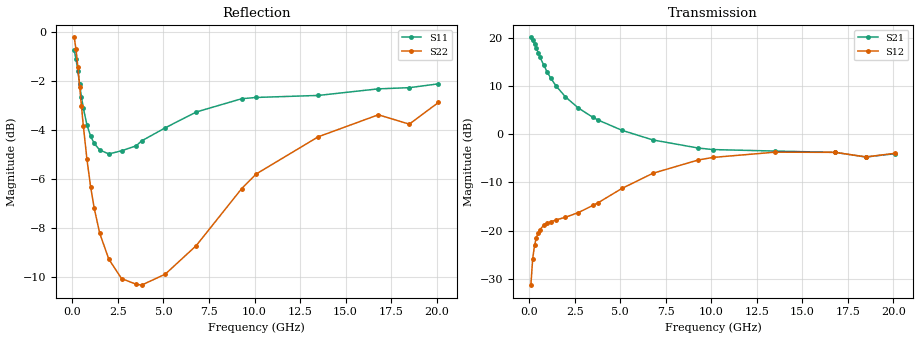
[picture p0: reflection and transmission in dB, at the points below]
!  Infineon Technologies AG
! BFR380L3 , PF131585-7, No.6, Th 09.10.01, soldered on pcb-board, measured with PP GSG850
!  Vce=5.0 V,  Ic=3.0 mA
! Common Emitter S-Parameters:  15. November 2001
#  GHz  S  MA  R  50
! f  S11  S21  S12  S22
! GHz  Mag  Ang  Mag  Ang  Mag  Ang  Mag  Ang
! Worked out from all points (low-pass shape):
!   201 points, 100 MHz to 20.1 GHz, reference 50 ohm
!   highest |S21| = 20.15 dB at 100 MHz (marker M1); lowest = -4.7 dB at 18.5 GHz (marker M2)
!   |S21| within 3 dB of the highest: start of sweep to 482.3 MHz
!   lowest |S11| = -5.0 dB at 2 GHz (marker M3), VSWR 3.59, Z = 14 - j3.21 ohm
!   |S11| at or under -10 dB: nowhere
!   |S22| runs from -10.3 to -0.2 dB; largest |S21 - S12| = 10
!   S11 on the Smith chart (normalised r, x): 100 MHz: 1.35, -5.37; 500 MHz: 0.33, -1.05; 1.2 GHz: 0.29, -0.34; 3.8 GHz: 0.27, +0.27; 9.3 GHz: 0.34, +1.07; 20.1 GHz: 0.99, +2.52
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0.1  0.9182 -19.9  10.17 166.1  0.02707 77.6  0.9756 -10.9
0.2  0.881 -38.7  9.463 153.6  0.05099 69.2  0.9223 -20.7
0.3  0.8326 -56.0  8.684 142.4  0.06991 60.6  0.8495 -28.9
0.4  0.7819 -71.0  7.851 132.9  0.08412 53.8  0.774 -35.5
0.5  0.7367 -84.2  7.068 124.9  0.0946 48.6  0.7051 -40.7
0.6  0.7 -95.4  6.367 118.2  0.1024 44.7  0.6443 -44.8
0.8  0.6466 -113.9  5.25 107.3  0.1128 39.5  0.55 -50.6
1  0.6131 -128.4  4.426 99.0  0.1192 36.6  0.4838 -54.5
1.2  0.5925 -140.2  3.808 92.1  0.1236 35.2  0.4367 -57.5
1.5  0.5746 -154.3  3.151 83.4  0.129 34.9  0.3885 -61.2
2  0.564 -172.0  2.447 71.7  0.1375 36.9  0.3439 -67.2
2.7  0.5724 169.6  1.881 58.2  0.1533 42.0  0.3139 -77.0
3.5  0.586 153.1  1.502 45.4  0.1823 47.4  0.3057 -89.7
3.8  0.5996 148.0  1.405 41.3  0.1948 48.8  0.3044 -95.9
5.1  0.6377 127.7  1.101 25.3  0.2737 49.8  0.3205 -121.4
6.8  0.6869 106.1  0.8736 10.7  0.3934 42.3  0.3665 -157.9
9.3  0.7313 83.0  0.7193 -1.6  0.5415 23.7  0.4794 158.0
10.1  0.7356 76.9  0.6938 -4.8  0.575 17.4  0.5135 145.9
13.5  0.7426 58.6  0.6698 -18.1  0.6521 -7.0  0.6114 106.9
16.8  0.7659 47.3  0.6488 -30.2  0.6492 -24.5  0.678 81.2
18.5  0.7702 45.5  0.5807 -37.9  0.582 -33.2  0.6488 74.6
20.1  0.7842 38.5  0.6293 -42.0  0.6348 -38.5  0.7185 63.2
